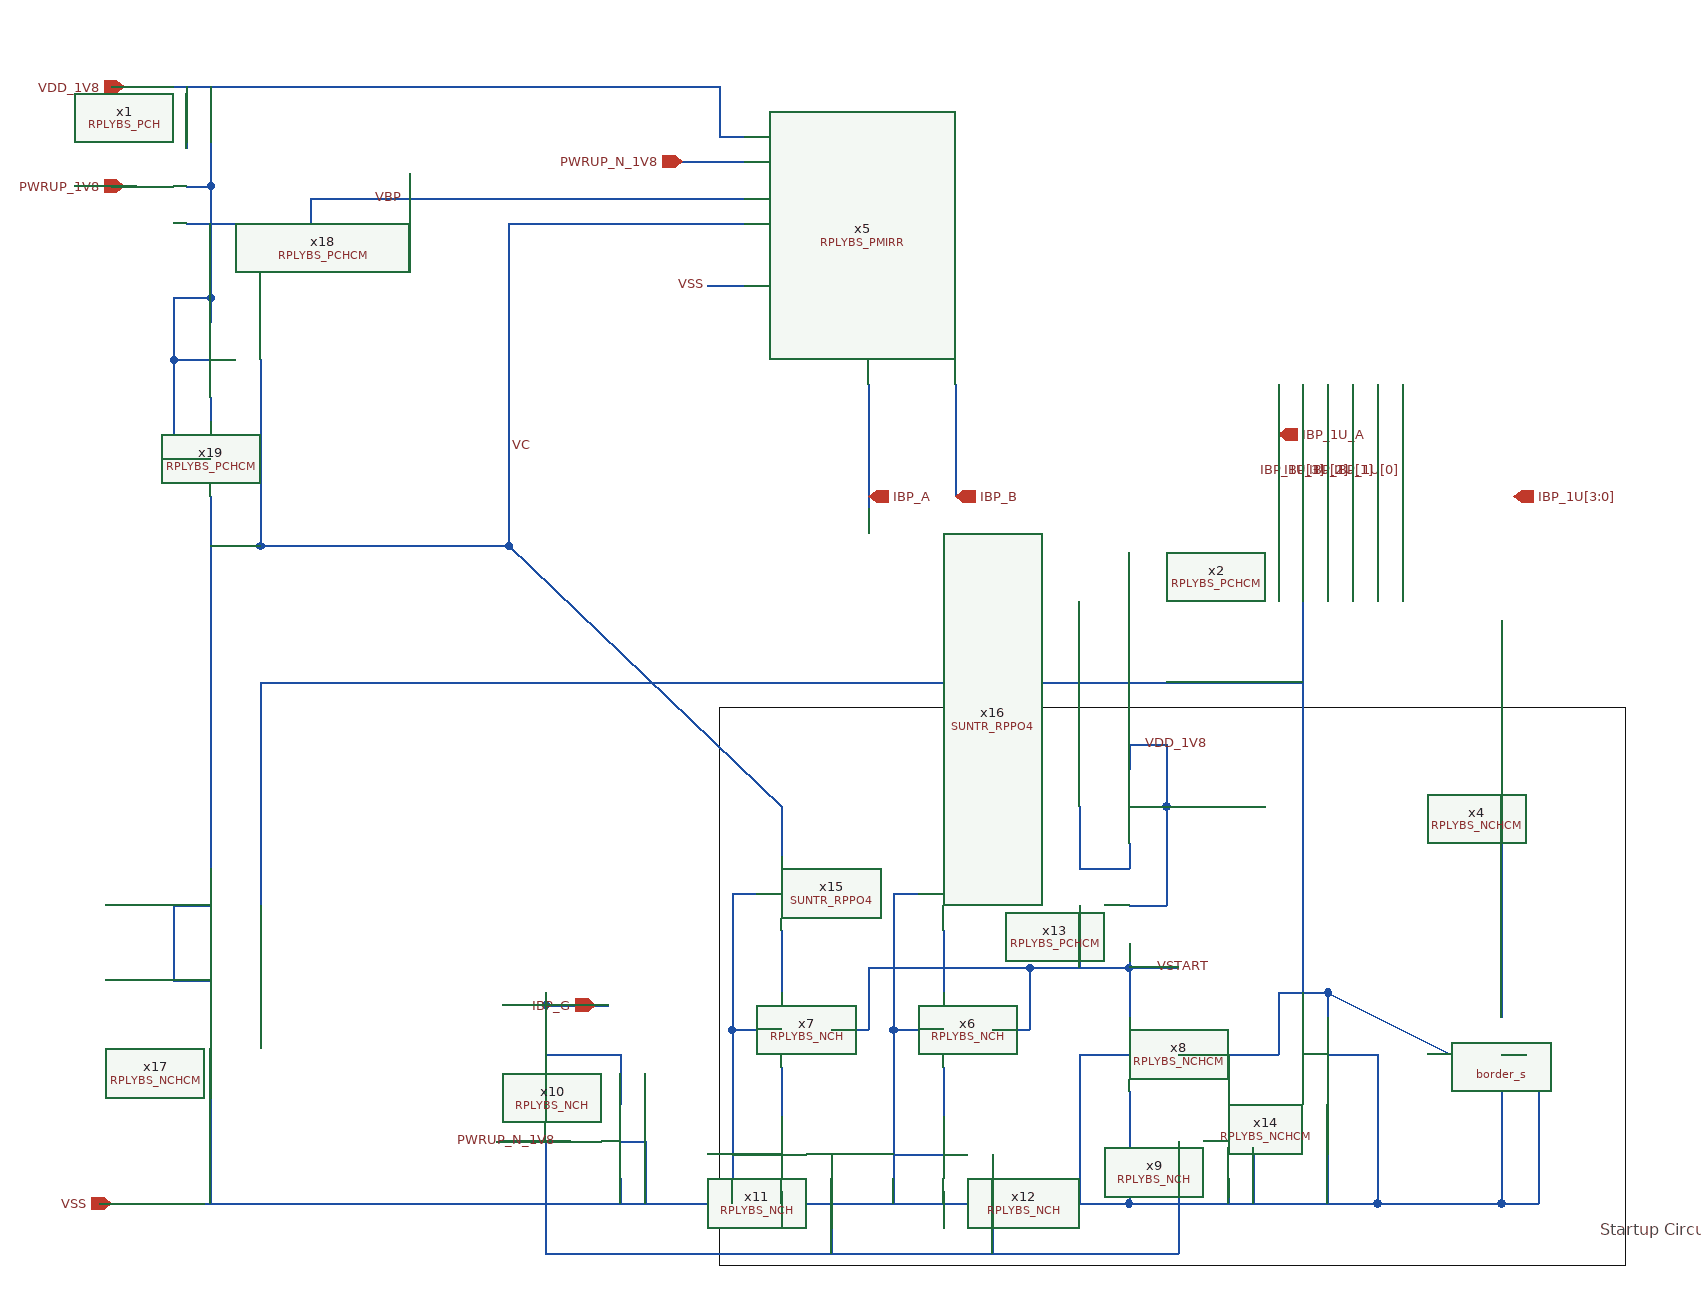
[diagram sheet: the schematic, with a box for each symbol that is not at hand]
v {xschem version=3.1.0 file_version=1.2 }
G {}
K {}
V {}
S {}
E {}
L 3 -110 -340 620 -340 {}
L 3 -110 -340 -110 110 {}
L 3 620 -340 620 110 {}
L 3 -110 110 620 110 {}
T {Startup Circuit} 600 70 0 1 0.4 0.4 {}
N -470 -840 -290 -840 {
lab=VDD_1V8}
N -600 -840 -470 -840 {
lab=VDD_1V8}
N -610 60 -370 60 {
lab=VSS}
N 440 -600 440 -500 {
lab=IBP_1U[0]}
N 420 -600 420 -500 {
lab=IBP_1U[1]}
N 400 -600 400 -500 {
lab=IBP_1U[2]}
N 380 -600 380 -500 {
lab=IBP_1U[3]}
N 220 -30 220 60 {
lab=VSS}
N 220 -260 250 -260 {
lab=VDD_1V8}
N 250 -310 250 -260 {
lab=VDD_1V8}
N 220 -310 220 -290 {
lab=VDD_1V8}
N 220 -140 220 -120 {
lab=VSTART}
N 220 -130 260 -130 {
lab=VSTART}
N 220 -310 250 -310 {
lab=VDD_1V8}
N 180 -260 180 -210 {
lab=#net1}
N 180 -210 220 -210 {
lab=#net1}
N 220 -230 220 -210 {
lab=#net1}
N 220 -150 220 -130 {
lab=VSTART}
N 220 -140 220 -130 {
lab=VSTART}
N 220 -120 220 -90 {
lab=VSTART}
N 220 60 230 60 {
lab=VSS}
N -370 60 220 60 {
lab=VSS}
N 10 -600 10 -500 {
lab=IBP_A}
N 80 -600 80 -510 {
lab=IBP_B}
N 340 -600 340 -560 {
lab=IBP_1U_A}
N -120 -680 -90 -680 {
lab=VSS}
N -110 -800 -90 -800 {
lab=VDD_1V8}
N -110 -840 -110 -800 {
lab=VDD_1V8}
N -140 -780 -90 -780 {
lab=PWRUP_N_1V8}
N -210 -840 -110 -840 {
lab=VDD_1V8}
N -290 -840 -210 -840 {
lab=VDD_1V8}
N -440 -750 -90 -750 {
lab=VBP}
N 360 -600 360 -500 {
lab=#net2}
N 230 60 250 60 {
lab=VSS}
N 30 -80 70 -80 {
lab=VSS}
N 30 -80 30 60 {
lab=VSS}
N 110 -80 140 -80 {
lab=VSTART}
N -250 -100 -200 -100 {
lab=IBP_G}
N 180 -60 220 -60 {
lab=VSS}
N 180 -60 180 60 {
lab=VSS}
N 380 -60 420 -60 {
lab=VSS}
N 420 -60 420 60 {
lab=VSS}
N 250 60 420 60 {
lab=VSS}
N 380 -30 380 60 {
lab=VSS}
N 340 -110 380 -110 {
lab=#net2}
N 340 -110 340 -60 {
lab=#net2}
N 260 -60 340 -60 {
lab=#net2}
N 360 -500 360 -110 {
lab=#net2}
N 380 -110 380 -90 {
lab=#net2}
N -250 -110 -250 -100 {
lab=IBP_G}
N -290 10 -230 10 {
lab=PWRUP_N_1V8}
N -190 10 -170 10 {
lab=VSS}
N -170 10 -170 60 {
lab=VSS}
N -190 40 -190 60 {
lab=VSS}
N -190 -60 -190 -20 {
lab=IBP_G}
N -250 -60 -190 -60 {
lab=IBP_G}
N -250 -100 -250 -60 {
lab=IBP_G}
N -100 -80 -60 -80 {
lab=VSS}
N -100 -80 -100 60 {
lab=VSS}
N -20 -80 10 -80 {
lab=VSTART}
N 140 -130 140 -80 {
lab=VSTART}
N 300 10 320 10 {
lab=VSS}
N 320 10 320 60 {
lab=VSS}
N 300 40 300 60 {
lab=VSS}
N 300 -60 300 -20 {
lab=#net2}
N -250 10 -250 100 {
lab=PWRUP_N_1V8}
N -250 100 260 100 {
lab=PWRUP_N_1V8}
N 260 10 260 100 {
lab=PWRUP_N_1V8}
N 70 -160 70 -110 {
lab=#net3}
N -60 -160 -60 -110 {
lab=#net4}
N -60 -260 -60 -220 {
lab=VC}
N 10 -130 140 -130 {
lab=VSTART}
N 140 -130 220 -130 {
lab=VSTART}
N 180 -180 180 -130 {
lab=VSTART}
N 220 -180 250 -180 {
lab=VDD_1V8}
N 250 -260 250 -180 {
lab=VDD_1V8}
N 70 50 70 60 {
lab=VSS}
N 70 -50 70 -10 {
lab=#net5}
N -60 50 -60 60 {
lab=VSS}
N -60 -50 -60 -10 {
lab=#net6}
N 10 -130 10 -80 {
lab=VSTART}
N 380 -110 480 -60 {
lab=#net2}
N 520 -30 520 60 {
lab=VSS}
N 420 60 520 60 {
lab=VSS}
N 520 -60 550 -60 {
lab=VSS}
N 550 -60 550 60 {
lab=VSS}
N 520 60 550 60 {
lab=VSS}
N 520 -410 520 -90 {
lab=#net7}
N -360 -770 -360 -750 {
lab=VBP}
N -100 20 -60 20 {
lab=VSS}
N -20 20 -20 100 {
lab=PWRUP_N_1V8}
N 30 20 70 20 {
lab=VSS}
N 110 20 110 100 {
lab=PWRUP_N_1V8}
N 30 -190 50 -190 {
lab=VSS}
N 30 -190 30 -80 {
lab=VSS}
N -100 -190 -100 -80 {
lab=VSS}
N -100 -190 -80 -190 {
lab=VSS}
N -280 -730 -280 -530 {
lab=VC}
N -280 -730 -90 -730 {
lab=VC}
N -540 -840 -540 -790 {
lab=VDD_1V8}
N -540 -760 -520 -760 {
lab=VDD_1V8}
N -520 -840 -520 -760 {
lab=VDD_1V8}
N -540 -730 -440 -730 {
lab=VBP}
N -440 -750 -440 -730 {
lab=VBP}
N -600 -760 -580 -760 {
lab=PWRUP_1V8}
N -520 -150 -520 60 {
lab=VSS}
N -550 -180 -520 -180 {
lab=VSS}
N -550 -180 -550 -120 {
lab=VSS}
N -550 -120 -520 -120 {
lab=VSS}
N -550 -620 -520 -620 {
lab=VDD_1V8}
N -550 -670 -550 -620 {
lab=VDD_1V8}
N -550 -670 -520 -670 {
lab=VDD_1V8}
N -520 -670 -520 -660 {
lab=VDD_1V8}
N -520 -660 -520 -650 {
lab=VDD_1V8}
N -520 -760 -520 -670 {
lab=VDD_1V8}
N -520 -590 -520 -570 {
lab=#net8}
N -550 -620 -550 -540 {
lab=VDD_1V8}
N -550 -540 -520 -540 {
lab=VDD_1V8}
N -520 -510 -520 -210 {
lab=VC}
N -480 -540 -480 -470 {
lab=VC}
N -520 -470 -480 -470 {
lab=VC}
N -480 -620 -480 -540 {
lab=VC}
N -480 -470 -280 -470 {
lab=VC}
N -280 -530 -280 -470 {
lab=VC}
N -480 -360 -480 -180 {
lab=#net2}
N -480 -360 360 -360 {
lab=#net2}
N -280 -470 -60 -260 {
lab=VC}
C {cborder/border_s.sym} 510 0 0 0 {
user="Carsten Wulff"
company="Carsten Wulff Software"}
C {devices/ipin.sym} -590 -840 0 0 {name=p1 lab=VDD_1V8}
C {devices/ipin.sym} -600 60 0 0 {name=p2 lab=VSS}
C {devices/opin.sym} 530 -510 0 0 {name=p8 lab=IBP_1U[3:0]}
C {devices/lab_pin.sym} -280 -550 0 1 {name=l12 sig_type=std_logic lab=VC}
C {devices/lab_wire.sym} 440 -530 1 1 {name=l11 sig_type=std_logic lab=IBP_1U[0]}
C {devices/lab_wire.sym} 420 -530 1 1 {name=l14 sig_type=std_logic lab=IBP_1U[1]}
C {devices/lab_wire.sym} 400 -530 1 1 {name=l15 sig_type=std_logic lab=IBP_1U[2]}
C {devices/lab_wire.sym} 380 -530 1 1 {name=l16 sig_type=std_logic lab=IBP_1U[3]}
C {devices/opin.sym} 340 -560 1 0 {name=p3 lab=IBP_1U_A}
C {devices/opin.sym} 10 -510 1 0 {name=p5 lab=IBP_A}
C {devices/opin.sym} 80 -510 1 0 {name=p6 lab=IBP_B}
C {devices/ipin.sym} -210 -100 2 0 {name=p7 lab=IBP_G}
C {devices/lab_wire.sym} 240 -130 0 1 {name=l1 sig_type=std_logic lab=VSTART}
C {devices/ipin.sym} -590 -760 0 0 {name=p9 lab=PWRUP_1V8}
C {devices/ipin.sym} -140 -780 0 0 {name=p10 lab=PWRUP_N_1V8}
C {RPLY_BIAS_SKY130NM/RPLYBS_PMIRR.sym} -70 -810 0 0 {name=x5 }
C {devices/lab_wire.sym} -120 -680 0 0 {name=l4 sig_type=std_logic lab=VSS}
C {RPLY_BIAS_SKY130NM/RPLYBS_PCHCM.sym} 180 -260 0 0 {name=x2 }
C {devices/lab_wire.sym} 230 -310 0 1 {name=l3 sig_type=std_logic lab=VDD_1V8}
C {devices/lab_wire.sym} -390 -750 0 1 {name=l6 sig_type=std_logic lab=VBP}
C {RPLY_BIAS_SKY130NM/RPLYBS_NCH.sym} 110 -80 0 1 {name=x6 }
C {RPLY_BIAS_SKY130NM/RPLYBS_NCHCM.sym} 340 -60 0 0 {name=x14 }
C {RPLY_BIAS_SKY130NM/RPLYBS_NCH.sym} -230 10 0 0 {name=x10 }
C {devices/lab_wire.sym} -240 10 0 0 {name=l2 sig_type=std_logic lab=PWRUP_N_1V8}
C {RPLY_BIAS_SKY130NM/RPLYBS_NCH.sym} -20 -80 0 1 {name=x7 }
C {RPLY_BIAS_SKY130NM/RPLYBS_NCH.sym} 260 10 0 0 {name=x9 }
C {RPLY_BIAS_SKY130NM/RPLYBS_NCHCM.sym} 260 -60 0 1 {name=x8 }
C {RPLY_BIAS_SKY130NM/RPLYBS_PCHCM.sym} 180 -180 0 0 {name=x13 }
C {RPLY_BIAS_SKY130NM/RPLYBS_NCHCM.sym} 480 -60 0 0 {name=x4 }
C {RPLY_BIAS_SKY130NM/RPLYBS_NCH.sym} -20 20 0 1 {name=x11 }
C {RPLY_BIAS_SKY130NM/RPLYBS_NCH.sym} 110 20 0 1 {name=x12 }
C {SUN_TR_SKY130NM/SUNTR_RPPO4.sym} -60 -230 1 0 {name=x15 }
C {SUN_TR_SKY130NM/SUNTR_RPPO4.sym} 70 -230 1 0 {name=x16 }
C {RPLY_BIAS_SKY130NM/RPLYBS_PCH.sym} -580 -760 0 0 {name=x1 }
C {RPLY_BIAS_SKY130NM/RPLYBS_NCHCM.sym} -480 -180 0 1 {name=x17 }
C {RPLY_BIAS_SKY130NM/RPLYBS_PCHCM.sym} -480 -620 0 1 {name=x18 }
C {RPLY_BIAS_SKY130NM/RPLYBS_PCHCM.sym} -480 -540 0 1 {name=x19 }
